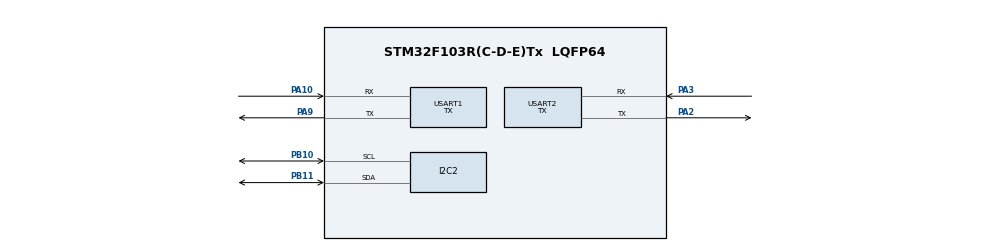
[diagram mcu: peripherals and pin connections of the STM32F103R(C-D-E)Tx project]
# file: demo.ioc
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I2C2.I2C_Mode=I2C_Standard
I2C2.NoStretchMode=I2C_NOSTRETCH_DISABLE
Mcu.Family=STM32F1
Mcu.Name=STM32F103R(C-D-E)Tx
Mcu.Package=LQFP64
NVIC.PriorityGroup=NVIC_PRIORITYGROUP_4
NVIC.USART1_IRQn=true\:0\:0\:false\:false\:true\:true\:true\:true
PA10.Mode=Asynchronous
PA10.Signal=USART1_RX
PA13.Mode=Serial_Wire
PA13.Signal=SYS_JTMS-SWDIO
PA14.Mode=Serial_Wire
PA14.Signal=SYS_JTCK-SWCLK
PA2.Mode=Asynchronous
PA2.Signal=USART2_TX
PA3.Mode=Asynchronous
PA3.Signal=USART2_RX
PA9.Mode=Asynchronous
PA9.Signal=USART1_TX
PB10.GPIO_Pu=GPIO_PULLUP
PB10.Mode=I2C
PB10.Signal=I2C2_SCL
PB11.GPIO_Pu=GPIO_PULLUP
PB11.Mode=I2C
PB11.Signal=I2C2_SDA
PD0-OSC_IN.Mode=HSE-External-Oscillator
PD0-OSC_IN.Signal=RCC_OSC_IN
PD1-OSC_OUT.Mode=HSE-External-Oscillator
PD1-OSC_OUT.Signal=RCC_OSC_OUT
ProjectManager.HeapSize=0x200
ProjectManager.StackSize=0x400
ProjectManager.TargetToolchain=MDK-ARM V5
RCC.AHBFreq_Value=72000000
RCC.APB1CLKDivider=RCC_HCLK_DIV2
RCC.APB1Freq_Value=36000000
RCC.APB1TimFreq_Value=72000000
RCC.APB2Freq_Value=72000000
RCC.APB2TimFreq_Value=72000000
RCC.HCLKFreq_Value=72000000
RCC.PLLMUL=RCC_PLL_MUL9
RCC.PLLSourceVirtual=RCC_PLLSOURCE_HSE
RCC.SYSCLKFreq_VALUE=72000000
RCC.SYSCLKSource=RCC_SYSCLKSOURCE_PLLCLK
RCC.USBFreq_Value=72000000
USART1.Mode=MODE_TX
USART1.VirtualMode=VM_ASYNC
USART2.Mode=MODE_TX
USART2.VirtualMode=VM_ASYNC
board=custom

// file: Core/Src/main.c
/* USER CODE BEGIN Header */
/**
 ******************************************************************************
 * @file           : main.c
 * @brief          : Main program body
 ******************************************************************************
 * @attention
 *
 * <h2><center>&copy; Copyright (c) 2022 STMicroelectronics.
 * All rights reserved.</center></h2>
 *
 * This software component is licensed by ST under BSD 3-Clause license,
 * the "License"; You may not use this file except in compliance with the
 * License. You may obtain a copy of the License at:
 *                        opensource.org/licenses/BSD-3-Clause
 *
 ******************************************************************************
 */
/* USER CODE END Header */
#include "main.h"
#include "i2c.h"
#include "usart.h"
#include "gpio.h"

/* USER CODE BEGIN Includes */
#include "ina219/ina219.h"

/* USER CODE END Includes */

void SystemClock_Config(void);

int main(void)
{

    /* MCU Configuration--------------------------------------------------------*/

    /* Reset of all peripherals, Initializes the Flash interface and the Systick. */
    HAL_Init();

    /* Configure the system clock */
    SystemClock_Config();

    /* Initialize all configured peripherals */
    MX_GPIO_Init();
    MX_USART1_UART_Init();
    MX_I2C2_Init();
    MX_USART2_UART_Init();

    /* Infinite loop */
    /* USER CODE BEGIN WHILE */

    struct ina219_dev ina219;

    ina219.bus        = &hi2c2;
    ina219.drv        = &hwi2c_drv;
    ina219.dev        = INA219_ADDRESS_0;
    ina219.ops        = I2C_DEV_7BIT | I2C_REG_8BIT;

    ina219.resistance = 0.1;  // 100R

    i2cdrv_detector(ina219.bus, ina219.drv);

    if (!i2cdev_check((i2c_cli_t)&ina219)) {
        i2cdrv_detector(ina219.bus, ina219.drv);
        while (1) {}
    } else {
        ina219_set_bus_voltage_range(&ina219, INA219_BUS_VOLTAGE_RANGE_32V);
        ina219_set_bus_voltage_adc_mode(&ina219, INA219_ADC_MODE_12_BIT_1_SAMPLES);
        ina219_set_shunt_voltage_adc_mode(&ina219, INA219_ADC_MODE_12_BIT_1_SAMPLES);
        ina219_set_mode(&ina219, INA219_MODE_SHUNT_BUS_VOLTAGE_CONTINUOUS);
        ina219_set_pga(&ina219, INA219_PGA_320_MV);
        uint16_t cal = ina219_calculate_calibration(&ina219);
        if (cal == 0) {
            println("fail to calculate calibration");
            while (1) {}
        }
        ina219_set_calibration(&ina219, cal);
    }

    while (1) {
        float mV = ina219_read_bus_voltage(&ina219, 0);
        float mA = ina219_read_current(&ina219, 0);
        float mW = ina219_read_power(&ina219, 0);
        println("%f,%f,%f,%f", mV, mA, mV, mA * mV);
        /* USER CODE END WHILE */

    }
}

void SystemClock_Config(void)
{
    RCC_OscInitTypeDef RCC_OscInitStruct = {0};
    RCC_ClkInitTypeDef RCC_ClkInitStruct = {0};

    /** Initializes the RCC Oscillators according to the specified parameters
     * in the RCC_OscInitTypeDef structure.
     */
    RCC_OscInitStruct.OscillatorType     = RCC_OSCILLATORTYPE_HSE;
    RCC_OscInitStruct.HSEState           = RCC_HSE_ON;
    RCC_OscInitStruct.HSEPredivValue     = RCC_HSE_PREDIV_DIV1;
    RCC_OscInitStruct.HSIState           = RCC_HSI_ON;
    RCC_OscInitStruct.PLL.PLLState       = RCC_PLL_ON;
    RCC_OscInitStruct.PLL.PLLSource      = RCC_PLLSOURCE_HSE;
    RCC_OscInitStruct.PLL.PLLMUL         = RCC_PLL_MUL2;
    if (HAL_RCC_OscConfig(&RCC_OscInitStruct) != HAL_OK) {
        Error_Handler();
    }

    /** Initializes the CPU, AHB and APB buses clocks
     */
    RCC_ClkInitStruct.ClockType      = RCC_CLOCKTYPE_HCLK | RCC_CLOCKTYPE_SYSCLK | RCC_CLOCKTYPE_PCLK1 | RCC_CLOCKTYPE_PCLK2;
    RCC_ClkInitStruct.SYSCLKSource   = RCC_SYSCLKSOURCE_PLLCLK;
    RCC_ClkInitStruct.AHBCLKDivider  = RCC_SYSCLK_DIV4;
    RCC_ClkInitStruct.APB1CLKDivider = RCC_HCLK_DIV2;
    RCC_ClkInitStruct.APB2CLKDivider = RCC_HCLK_DIV1;

    if (HAL_RCC_ClockConfig(&RCC_ClkInitStruct, FLASH_LATENCY_0) != HAL_OK) {
        Error_Handler();
    }
}

void Error_Handler(void)
{
}
